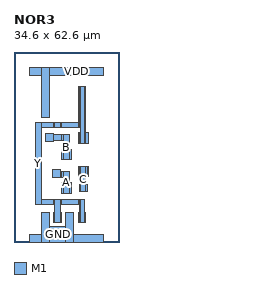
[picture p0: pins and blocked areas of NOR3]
MACRO NOR3
  CLASS CORE ;
  ORIGIN 0 0 ;
  SIZE 34.600 BY 62.600 ;
  SYMMETRY X Y ;
  SITE TR1um_site ;
  PIN Y
    DIRECTION OUTPUT ;
    USE SIGNAL ;
    PORT
      LAYER M1 ;
        RECT 7.100 12.300 8.900 39.500 ;
      LAYER M1 ;
        RECT 8.900 12.300 13.100 14.100 ;
      LAYER M1 ;
        RECT 8.900 37.700 13.100 39.500 ;
      LAYER M1 ;
        RECT 13.100 6.400 13.500 9.800 ;
      LAYER M1 ;
        RECT 13.100 12.300 13.500 14.100 ;
      LAYER M1 ;
        RECT 13.100 37.700 13.500 39.500 ;
      LAYER M1 ;
        RECT 13.500 6.400 15.300 14.100 ;
      LAYER M1 ;
        RECT 13.500 37.700 15.300 39.500 ;
      LAYER M1 ;
        RECT 15.300 6.400 15.700 9.800 ;
      LAYER M1 ;
        RECT 15.300 12.300 15.700 14.100 ;
      LAYER M1 ;
        RECT 15.300 37.700 15.700 39.500 ;
      LAYER M1 ;
        RECT 15.700 12.300 21.100 14.100 ;
      LAYER M1 ;
        RECT 15.700 37.700 21.100 39.500 ;
      LAYER M1 ;
        RECT 21.100 6.400 21.500 9.800 ;
      LAYER M1 ;
        RECT 21.100 12.300 21.500 14.100 ;
      LAYER M1 ;
        RECT 21.100 32.600 21.500 36.000 ;
      LAYER M1 ;
        RECT 21.100 37.700 21.500 51.200 ;
      LAYER M1 ;
        RECT 21.500 6.400 21.900 14.100 ;
      LAYER M1 ;
        RECT 21.500 32.600 21.900 36.000 ;
      LAYER M1 ;
        RECT 21.500 37.700 21.900 51.200 ;
      LAYER M1 ;
        RECT 21.900 6.400 23.300 14.100 ;
      LAYER M1 ;
        RECT 21.900 32.600 23.300 51.200 ;
      LAYER M1 ;
        RECT 23.300 6.400 23.700 9.800 ;
      LAYER M1 ;
        RECT 23.300 32.600 23.700 51.200 ;
      LAYER M1 ;
        RECT 23.700 32.600 24.500 36.000 ;
    END
  END Y
  PIN A
    DIRECTION INPUT ;
    USE SIGNAL ;
    PORT
      LAYER M1 ;
        RECT 12.600 21.300 15.200 23.900 ;
      LAYER M1 ;
        RECT 15.200 21.300 15.600 23.100 ;
      LAYER M1 ;
        RECT 15.600 16.100 16.400 19.500 ;
      LAYER M1 ;
        RECT 15.600 21.300 16.400 23.100 ;
      LAYER M1 ;
        RECT 16.400 16.100 18.200 23.100 ;
      LAYER M1 ;
        RECT 18.200 16.100 19.000 19.500 ;
    END
  END A
  PIN B
    DIRECTION INPUT ;
    USE SIGNAL ;
    PORT
      LAYER M1 ;
        RECT 10.400 33.100 13.000 35.700 ;
      LAYER M1 ;
        RECT 13.000 33.500 15.600 35.300 ;
      LAYER M1 ;
        RECT 15.600 27.100 16.400 30.500 ;
      LAYER M1 ;
        RECT 15.600 33.500 16.400 35.300 ;
      LAYER M1 ;
        RECT 16.400 27.100 18.200 35.300 ;
      LAYER M1 ;
        RECT 18.200 27.100 19.000 30.500 ;
    END
  END B
  PIN C
    DIRECTION INPUT ;
    USE SIGNAL ;
    PORT
      LAYER M1 ;
        RECT 21.100 21.600 21.500 25.000 ;
      LAYER M1 ;
        RECT 21.500 16.500 21.900 19.100 ;
      LAYER M1 ;
        RECT 21.500 21.600 21.900 25.000 ;
      LAYER M1 ;
        RECT 21.900 16.500 23.700 25.000 ;
      LAYER M1 ;
        RECT 23.700 16.500 24.100 19.100 ;
      LAYER M1 ;
        RECT 23.700 21.600 24.100 25.000 ;
      LAYER M1 ;
        RECT 24.100 21.600 24.500 25.000 ;
    END
  END C
  PIN VDD
    DIRECTION INOUT ;
    USE POWER ;
    PORT
      LAYER M1 ;
        RECT 5.000 55.000 9.100 57.600 ;
      LAYER M1 ;
        RECT 9.100 41.000 11.700 57.600 ;
      LAYER M1 ;
        RECT 11.700 55.000 29.600 57.600 ;
    END
  END VDD
  PIN GND
    DIRECTION INOUT ;
    USE GROUND ;
    PORT
      LAYER M1 ;
        RECT 5.000 0.000 9.100 2.600 ;
      LAYER M1 ;
        RECT 9.100 0.000 11.700 9.800 ;
      LAYER M1 ;
        RECT 11.700 0.000 17.100 5.000 ;
      LAYER M1 ;
        RECT 17.100 0.000 19.700 9.800 ;
      LAYER M1 ;
        RECT 19.700 0.000 29.600 2.600 ;
    END
  END GND
END NOR3
